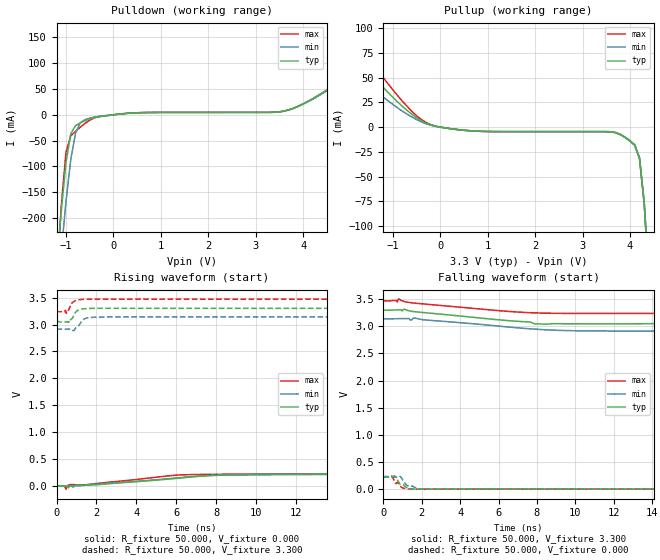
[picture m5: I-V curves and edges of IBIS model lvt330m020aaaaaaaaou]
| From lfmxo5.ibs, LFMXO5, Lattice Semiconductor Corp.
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|Model lvt330m020aaaaaaaaou
[Model] lvt330m020aaaaaaaaou
Model_type Output
Polarity   Non-Inverting
Enable   Active-High
Vmeas =  1.650V
Cref =  0.0F
Rref =  1.000M
Vref =  0.0V
C_comp   5.000pF   4.000pF   5.500pF
[Temperature Range]   25.000   0.125k   -40.000
[Voltage Range]   3.300V   3.140V   3.470V
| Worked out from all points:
|   slope of the pulldown table from 0 to 0.495 V, typ, clamps not added: 127 ohm
|   slope of the pullup table from 0 to 0.495 V, typ, clamps not added: 157 ohm
|   rising waveform, R_fixture 50.000, V_fixture 0.000: 20-80 % time 4.54ns typ, 4.56ns min, 3.49ns max; typ from 0.001 V to 0.23 V
|   rising waveform, R_fixture 50.000, V_fixture 3.300: 20-80 % time 255ps typ, 316ps min, 225ps max; typ from 3.07 V to 3.3 V
|   falling waveform, R_fixture 50.000, V_fixture 3.300: 20-80 % time 4.11ns typ, 4.44ns min, 4.42ns max; typ from 3.3 V to 3.07 V
|   falling waveform, R_fixture 50.000, V_fixture 0.000: 20-80 % time 424ps typ, 568ps min, 378ps max; typ from 0.23 V to 0.001 V
[Pulldown]
|Voltage   I(typ)   I(min)   I(max)
-3.3V     -3.023A    -2.882A    -4.076A
-1.2V     -299.4mA   -373.4mA   -326mA
-1.1V     -186.9mA   -266.3mA   -176.8mA
-1V       -92.5mA    -167.9mA   -72.23mA
-900mV    -37.01mA   -86.9mA    -41.16mA
-800mV    -21.11mA   -36.05mA   -32.24mA
-600mV    -11.54mA   -9.523mA   -16.85mA
300mV     2.85mA     2.764mA    2.85mA
3.7V      9.528mA    9.243mA    9.528mA
5.3V      94.4mA     91.6mA     94.4mA
6.1V      116.9mA    113.4mA    116.9mA
6.6V      170.2mA    165.1mA    170.2mA
[Pullup]
|Voltage   I(typ)   I(min)   I(max)
-3.3V     139.8mA    86.3mA     180mA
-2.9V     101.3mA    74.5mA     141.2mA
-2.7V     91.2mA     69.71mA    121.2mA
-2.1V     82mA       60.12mA    100.7mA
-700mV    16.87mA    13.06mA    20.99mA
-200mV    2.224mA    1.901mA    2.518mA
3.8V      -7.608mA   -7.38mA    -7.608mA
4.1V      -18.4mA    -17.85mA   -18.4mA
4.2V      -31.66mA   -30.71mA   -31.66mA
4.3V      -78.1mA    -75.8mA    -78.1mA
4.4V      -157.4mA   -152.7mA   -157.4mA
6.6V      -2.541A    -2.465A    -2.541A
[Ramp]
| variable   typ   min   max
dV/dt_r   0.137/4.537n   0.132/4.570n   0.137/3.489n
dV/dt_f   0.140/4.121n   0.140/4.439n   0.140/4.430n
R_load = 50.000
[Rising Waveform]
R_fixture = 50.000
V_fixture = 0.000
V_fixture_min = 0.000
V_fixture_max = 0.000
|  time   V(typ)   V(min)   V(max)
0s        974.6uV    2.808mV    974.6uV
395ps     1.014mV    2.541mV    3.245mV
474ps     1.094mV    2.743mV    -54mV
551ps     18.37uV    2.846mV    10.16mV
600ps     -28.6mV    2.882mV    23.28mV
694ps     4.479mV    2.82mV     32.36mV
1.471ns   19.01mV    22.34mV    28.71mV
6.379ns   159mV      165.3mV    212.4mV
9.019ns   214.7mV    208.7mV    223.8mV
20ns      230mV      223mV      230mV
[Rising Waveform]
R_fixture = 50.000
V_fixture = 3.300
V_fixture_min = 3.140
V_fixture_max = 3.470
|  time   V(typ)   V(min)   V(max)
0s        3.067V     2.914V     3.238V
403ps     3.047V     2.913V     3.233V
445ps     3.047V     2.914V     3.263V
500ps     3.047V     2.914V     3.208V
662ps     3.041V     2.914V     3.318V
681ps     3.079V     2.914V     3.336V
852ps     3.159V     2.884V     3.424V
1.072ns   3.262V     2.967V     3.455V
1.472ns   3.295V     3.115V     3.469V
20ns      3.3V       3.14V      3.47V
[Falling Waveform]
R_fixture = 50.000
V_fixture = 3.300
V_fixture_min = 3.140
V_fixture_max = 3.470
|  time   V(typ)   V(min)   V(max)
0s        3.3V       3.14V      3.47V
670ps     3.303V     3.14V      3.481V
720ps     3.303V     3.141V     3.45V
800ps     3.303V     3.141V     3.503V
1.319ns   3.288V     3.144V     3.442V
1.439ns   3.279V     3.114V     3.436V
1.608ns   3.271V     3.152V     3.429V
7.648ns   3.08V      2.954V     3.251V
7.877ns   3.047V     2.948V     3.248V
20ns      3.067V     2.914V     3.238V
[Falling Waveform]
R_fixture = 50.000
V_fixture = 0.000
V_fixture_min = 0.000
V_fixture_max = 0.000
|  time   V(typ)   V(min)   V(max)
0s        230mV      223mV      230mV
440ps     229.7mV    222.7mV    240.8mV
596ps     241.2mV    222.5mV    132.5mV
650ps     221.4mV    222.9mV    101.4mV
750ps     159.3mV    231mV      126.2mV
840ps     106mV      238.6mV    74.79mV
1.241ns   22.21mV    65.97mV    3.745mV
1.412ns   6.578mV    61.12mV    468.3uV
2.312ns   -351.9uV   520.9uV    -691.9uV
20ns      974.6uV    2.808mV    974.6uV
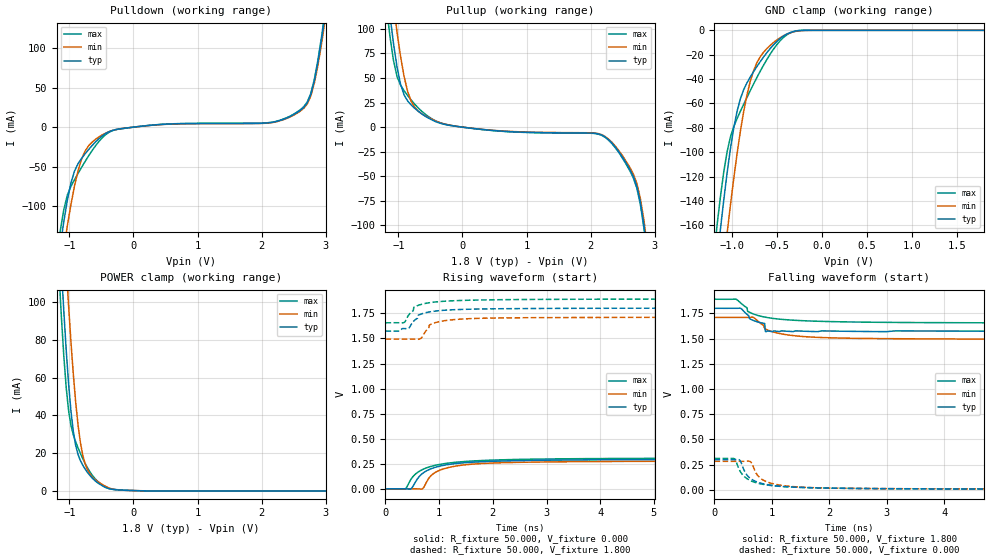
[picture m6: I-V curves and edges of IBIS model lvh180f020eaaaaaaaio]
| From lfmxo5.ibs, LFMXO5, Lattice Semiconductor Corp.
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[Model] lvh180f020eaaaaaaaio
Model_type I/O
Polarity   Non-Inverting
Enable   Active-Low
Vinl =  0.630V
Vinh =  1.170V
Vmeas =  0.900V
Cref =  0.0F
Rref =  1.000M
Vref =  0.0V
C_comp   5.000pF   4.000pF   5.500pF
[Temperature Range]   25.000   0.125k   -40.000
[Voltage Range]   1.800V   1.710V   1.890V
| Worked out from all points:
|   slope of the pulldown table from 0 to 0.27 V, typ, clamps not added: 114 ohm
|   slope of the pullup table from 0 to 0.27 V, typ, clamps not added: 129 ohm
|   GND clamp passes 1 mA (typ) near -0.32 V on its own axis
|   POWER clamp passes 1 mA (typ) near -0.38 V on its own axis
|   rising waveform, R_fixture 50.000, V_fixture 0.000: 20-80 % time 548ps typ, 506ps min, 585ps max; typ from 0.006 V to 0.3 V
|   rising waveform, R_fixture 50.000, V_fixture 1.800: 20-80 % time 293ps typ, 299ps min, 311ps max; typ from 1.57 V to 1.8 V
|   falling waveform, R_fixture 50.000, V_fixture 1.800: 20-80 % time 341ps typ, 511ps min, 523ps max; typ from 1.8 V to 1.57 V
|   falling waveform, R_fixture 50.000, V_fixture 0.000: 20-80 % time 329ps typ, 334ps min, 346ps max; typ from 0.3 V to 0.006 V
[GND_clamp]
|Voltage   I(typ)   I(min)   I(max)
-1.8V     -676.5mA   -711.8mA   -657.4mA
-1.171V   -188.8mA   -241.8mA   -160mA
-1.134V   -163.6mA   -216.3mA   -136.9mA
-1.06V    -117.6mA   -167.3mA   -100mA
-1.023V   -97.67mA   -144.1mA   -87.78mA
-949mV    -66.77mA   -101.8mA   -72.6mA
-875mV    -48.8mA    -66.89mA   -60.78mA
-801mV    -38.33mA   -41.86mA   -49.49mA
-690mV    -25.71mA   -21.72mA   -33.55mA
-468mV    -6.724mA   -6.036mA   -8.541mA
-246mV    -145.3uA   -325.1uA   -81.62uA
1.8V      0A         0A         0A
[POWER_clamp]
|Voltage   I(typ)   I(min)   I(max)
-1.8V     627.7mA    654.9mA    614.1mA
-1.16V    141.5mA    189mA      114.4mA
-1.123V   117.5mA    164.8mA    91.5mA
-1.086V   95.05mA    141.5mA    71.26mA
-1.049V   74.59mA    119.2mA    54.66mA
-1.012V   56.78mA    98.27mA    42.5mA
-938mV    31.33mA    61.69mA    29.59mA
-864mV    19.12mA    34.68mA    22.65mA
-790mV    13.42mA    18.68mA    16.91mA
-679mV    8.018mA    8.826mA    9.955mA
-494mV    2.695mA    3.4mA      3.109mA
3.6V      -185.9uA   -195.7uA   -188.2uA
[Pulldown]
|Voltage   I(typ)   I(min)   I(max)
-1.8V     -596.9mA   -586.3mA   -599.1mA
-1.14V    -149.8mA   -183.1mA   -130.3mA
-1.085V   -119mA     -153mA     -104.1mA
-1.03V    -92.1mA    -124.4mA   -85.91mA
-920mV    -55.83mA   -74.71mA   -66.66mA
-755mV    -33.93mA   -30.38mA   -43.67mA
-370mV    -5.457mA   -5.328mA   -6.03mA
2.105V    5.503mA    5.228mA    5.668mA
2.545V    18.25mA    17.33mA    18.79mA
2.765V    41.38mA    39.31mA    42.62mA
2.985V    140.5mA    133.5mA    144.7mA
3.6V      544.2mA    517mA      560.5mA
[Pullup]
|Voltage   I(typ)   I(min)   I(max)
-1.8V     561.9mA    586.2mA    549.8mA
-1.185V   145.6mA    187.1mA    122.3mA
-1.075V   85.04mA    124.6mA    67.76mA
-1.02V    61.14mA    96.8mA     51.55mA
-910mV    32.88mA    51.58mA    37.04mA
-800mV    22.6mA     26.38mA    27.65mA
-580mV    11.11mA    11.48mA    13.15mA
190mV     -1.523mA   -1.447mA   -1.569mA
2.17V     -8.019mA   -7.618mA   -8.259mA
2.665V    -50.16mA   -47.66mA   -51.67mA
2.83V     -99.5mA    -94.5mA    -102.5mA
3.6V      -645.6mA   -613.3mA   -665mA
[Ramp]
| variable   typ   min   max
dV/dt_r   0.182/0.563n   0.166/0.513n   0.183/0.586n
dV/dt_f   0.137/0.572n   0.130/0.594n   0.141/0.636n
R_load = 50.000
[Rising Waveform]
R_fixture = 50.000
V_fixture = 0.000
V_fixture_min = 0.000
V_fixture_max = 0.000
|  time   V(typ)   V(min)   V(max)
0s        6.423mV    6.572mV    6.562mV
364ps     6.676mV    6.656mV    6.008mV
467ps     5.014mV    6.631mV    94.25mV
558ps     74.13mV    6.756mV    152.9mV
677ps     153.5mV    5.196mV    194.5mV
837ps     203.1mV    130.8mV    227.3mV
966ps     225.7mV    180.3mV    244.2mV
1.607ns   270.4mV    250.9mV    282.1mV
3.441ns   292.8mV    275.5mV    304.9mV
10ns      299.8mV    282.8mV    311mV
[Rising Waveform]
R_fixture = 50.000
V_fixture = 1.800
V_fixture_min = 1.710
V_fixture_max = 1.890
|  time   V(typ)   V(min)   V(max)
0s        1.571V     1.492V     1.654V
257ps     1.571V     1.492V     1.655V
346ps     1.597V     1.492V     1.658V
435ps     1.602V     1.492V     1.734V
517ps     1.665V     1.492V     1.773V
527ps     1.671V     1.492V     1.807V
636ps     1.735V     1.493V     1.832V
846ps     1.764V     1.639V     1.855V
1.328ns   1.785V     1.688V     1.874V
10ns      1.8V       1.71V      1.89V
[Falling Waveform]
R_fixture = 50.000
V_fixture = 1.800
V_fixture_min = 1.710
V_fixture_max = 1.890
|  time   V(typ)   V(min)   V(max)
0s        1.8V       1.71V      1.89V
362ps     1.8V       1.71V      1.892V
457ps     1.8V       1.71V      1.853V
675ps     1.68V      1.71V      1.744V
875ps     1.649V     1.598V     1.713V
887ps     1.571V     1.595V     1.712V
900ps     1.569V     1.592V     1.71V
1.414ns   1.576V     1.527V     1.681V
2.345ns   1.572V     1.503V     1.665V
10ns      1.571V     1.492V     1.654V
[Falling Waveform]
R_fixture = 50.000
V_fixture = 0.000
V_fixture_min = 0.000
V_fixture_max = 0.000
|  time   V(typ)   V(min)   V(max)
0s        299.8mV    282.8mV    311mV
346ps     299.6mV    282.6mV    307.9mV
433ps     297.1mV    282.8mV    200.2mV
537ps     171.7mV    283mV      123.2mV
615ps     118.2mV    282mV      94.82mV
745ps     77.4mV     148.3mV    67.23mV
829ps     62.59mV    103.2mV    56.16mV
1.285ns   29.75mV    36.2mV     29.15mV
2.98ns    11.58mV    11.73mV    10.95mV
10ns      6.423mV    6.572mV    6.562mV
